VERSION 5.8 ;
BUSBITCHARS "[]" ;
DIVIDERCHAR "/" ;

PROPERTYDEFINITIONS
  LAYER contactResistance REAL ;
END PROPERTYDEFINITIONS

UNITS
  DATABASE MICRONS 2000 ;
END UNITS
MANUFACTURINGGRID 0.0025 ;
LAYER OVERLAP
  TYPE OVERLAP ;
END OVERLAP

LAYER poly
  TYPE MASTERSLICE ;
END poly

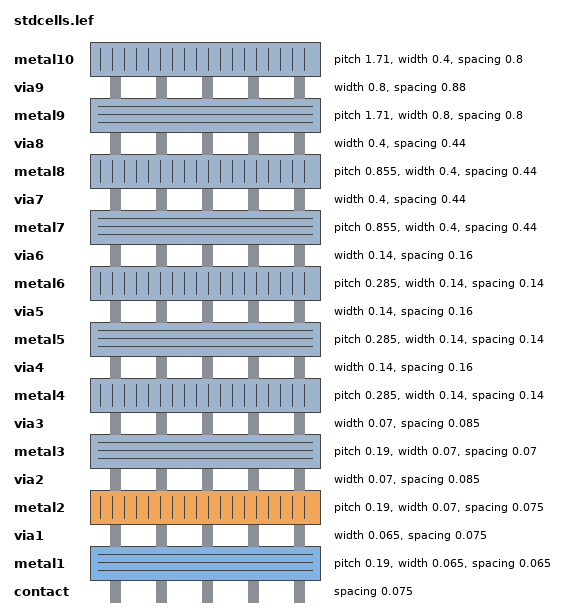
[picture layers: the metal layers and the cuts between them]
LAYER contact
  TYPE CUT ;
  SPACING 0.075 ;
  PROPERTY contactResistance 10.5 ;
END contact

LAYER metal1
  TYPE ROUTING ;
  DIRECTION HORIZONTAL ;
  PITCH 0.19 0.19 ;
  WIDTH 0.065 ;
  SPACING 0.065 ;
  SPACING 0.065 SAMENET ;
  RESISTANCE RPERSQ 0.38 ;
END metal1

LAYER via1
  TYPE CUT ;
  SPACING 0.075 ;
  WIDTH 0.065 ;
  PROPERTY contactResistance 5.69 ;
END via1

LAYER metal2
  TYPE ROUTING ;
  DIRECTION VERTICAL ;
  PITCH 0.19 0.19 ;
  WIDTH 0.07 ;
  SPACING 0.075 ;
  SPACING 0.07 SAMENET ;
  RESISTANCE RPERSQ 0.25 ;
END metal2

LAYER via2
  TYPE CUT ;
  SPACING 0.085 ;
  WIDTH 0.07 ;
  PROPERTY contactResistance 11.39 ;
END via2

LAYER metal3
  TYPE ROUTING ;
  DIRECTION HORIZONTAL ;
  PITCH 0.19 0.19 ;
  WIDTH 0.07 ;
  SPACING 0.07 ;
  SPACING 0.07 SAMENET ;
  RESISTANCE RPERSQ 0.25 ;
END metal3

LAYER via3
  TYPE CUT ;
  SPACING 0.085 ;
  WIDTH 0.07 ;
  PROPERTY contactResistance 16.73 ;
END via3

LAYER metal4
  TYPE ROUTING ;
  DIRECTION VERTICAL ;
  PITCH 0.285 0.285 ;
  WIDTH 0.14 ;
  SPACING 0.14 ;
  SPACING 0.14 SAMENET ;
  RESISTANCE RPERSQ 0.25 ;
END metal4

LAYER via4
  TYPE CUT ;
  SPACING 0.16 ;
  WIDTH 0.14 ;
  PROPERTY contactResistance 21.44 ;
END via4

LAYER metal5
  TYPE ROUTING ;
  DIRECTION HORIZONTAL ;
  PITCH 0.285 0.285 ;
  WIDTH 0.14 ;
  SPACING 0.14 ;
  SPACING 0.14 SAMENET ;
  RESISTANCE RPERSQ 0.25 ;
END metal5

LAYER via5
  TYPE CUT ;
  SPACING 0.16 ;
  WIDTH 0.14 ;
  PROPERTY contactResistance 24.08 ;
END via5

LAYER metal6
  TYPE ROUTING ;
  DIRECTION VERTICAL ;
  PITCH 0.285 0.285 ;
  WIDTH 0.14 ;
  SPACING 0.14 ;
  SPACING 0.14 SAMENET ;
  RESISTANCE RPERSQ 0.25 ;
END metal6

LAYER via6
  TYPE CUT ;
  SPACING 0.16 ;
  WIDTH 0.14 ;
  PROPERTY contactResistance 11.39 ;
END via6

LAYER metal7
  TYPE ROUTING ;
  DIRECTION HORIZONTAL ;
  PITCH 0.855 0.855 ;
  WIDTH 0.4 ;
  SPACING 0.44 ;
  SPACING 0.44 SAMENET ;
  RESISTANCE RPERSQ 0.25 ;
END metal7

LAYER via7
  TYPE CUT ;
  SPACING 0.44 ;
  WIDTH 0.4 ;
  PROPERTY contactResistance 5.69 ;
END via7

LAYER metal8
  TYPE ROUTING ;
  DIRECTION VERTICAL ;
  PITCH 0.855 0.855 ;
  WIDTH 0.4 ;
  SPACING 0.44 ;
  SPACING 0.44 SAMENET ;
  RESISTANCE RPERSQ 0.25 ;
END metal8

LAYER via8
  TYPE CUT ;
  SPACING 0.44 ;
  WIDTH 0.4 ;
  PROPERTY contactResistance 16.73 ;
END via8

LAYER metal9
  TYPE ROUTING ;
  DIRECTION HORIZONTAL ;
  PITCH 1.71 1.71 ;
  WIDTH 0.8 ;
  SPACING 0.8 ;
  SPACING 0.8 SAMENET ;
  RESISTANCE RPERSQ 0.21 ;
END metal9

LAYER via9
  TYPE CUT ;
  SPACING 0.88 ;
  WIDTH 0.8 ;
  PROPERTY contactResistance 21.44 ;
END via9

LAYER metal10
  TYPE ROUTING ;
  DIRECTION VERTICAL ;
  PITCH 1.71 1.71 ;
  WIDTH 0.4 ;
  SPACING 0.8 ;
  SPACING 0.8 SAMENET ;
  RESISTANCE RPERSQ 0.21 ;
END metal10

VIARULE M2_M1 GENERATE
  LAYER metal1 ;
    ENCLOSURE 0 0.035 ;
  LAYER metal2 ;
    ENCLOSURE 0 0.035 ;
  LAYER via1 ;
    RECT -0.0325 -0.0325 0.0325 0.0325 ;
    SPACING 0.14 BY 0.14 ;
END M2_M1

VIARULE M3_M2 GENERATE
  LAYER metal2 ;
    ENCLOSURE 0 0.035 ;
  LAYER metal3 ;
    ENCLOSURE 0 0.035 ;
  LAYER via2 ;
    RECT -0.035 -0.035 0.035 0.035 ;
    SPACING 0.155 BY 0.155 ;
END M3_M2

VIARULE M4_M3 GENERATE
  LAYER metal3 ;
    ENCLOSURE 0 0.035 ;
  LAYER metal4 ;
    ENCLOSURE 0 0 ;
  LAYER via3 ;
    RECT -0.035 -0.035 0.035 0.035 ;
    SPACING 0.155 BY 0.155 ;
END M4_M3

VIARULE M5_M4 GENERATE
  LAYER metal4 ;
    ENCLOSURE 0 0 ;
  LAYER metal5 ;
    ENCLOSURE 0 0 ;
  LAYER via4 ;
    RECT -0.07 -0.07 0.07 0.07 ;
    SPACING 0.3 BY 0.3 ;
END M5_M4

VIARULE M6_M5 GENERATE
  LAYER metal5 ;
    ENCLOSURE 0 0 ;
  LAYER metal6 ;
    ENCLOSURE 0 0 ;
  LAYER via5 ;
    RECT -0.07 -0.07 0.07 0.07 ;
    SPACING 0.3 BY 0.3 ;
END M6_M5

VIARULE M7_M6 GENERATE
  LAYER metal6 ;
    ENCLOSURE 0 0 ;
  LAYER metal7 ;
    ENCLOSURE 0.13 0.13 ;
  LAYER via6 ;
    RECT -0.07 -0.07 0.07 0.07 ;
    SPACING 0.3 BY 0.3 ;
END M7_M6

VIARULE M8_M7 GENERATE
  LAYER metal7 ;
    ENCLOSURE 0 0 ;
  LAYER metal8 ;
    ENCLOSURE 0 0 ;
  LAYER via7 ;
    RECT -0.2 -0.2 0.2 0.2 ;
    SPACING 0.8 BY 0.8 ;
END M8_M7

VIARULE M9_M8 GENERATE
  LAYER metal8 ;
    ENCLOSURE 0 0 ;
  LAYER metal9 ;
    ENCLOSURE 0.2 0.2 ;
  LAYER via8 ;
    RECT -0.2 -0.2 0.2 0.2 ;
    SPACING 0.8 BY 0.8 ;
END M9_M8

VIARULE M10_M9 GENERATE
  LAYER metal9 ;
    ENCLOSURE 0 0 ;
  LAYER metal10 ;
    ENCLOSURE 0 0 ;
  LAYER via9 ;
    RECT -0.4 -0.4 0.4 0.4 ;
    SPACING 1.6 BY 1.6 ;
END M10_M9

VIARULE M1_POLY GENERATE
  LAYER poly ;
    ENCLOSURE 0 0 ;
  LAYER metal1 ;
    ENCLOSURE 0 0.035 ;
  LAYER contact ;
    RECT -0.0325 -0.0325 0.0325 0.0325 ;
    SPACING 0.14 BY 0.14 ;
END M1_POLY

VIA M2_M1_via DEFAULT
  LAYER metal1 ;
    RECT -0.0675 -0.0325 0.0675 0.0325 ;
  LAYER via1 ;
    RECT -0.0325 -0.0325 0.0325 0.0325 ;
  LAYER metal2 ;
    RECT -0.035 -0.0675 0.035 0.0675 ;
END M2_M1_via

VIA M3_M2_via DEFAULT
  LAYER metal2 ;
    RECT -0.035 -0.07 0.035 0.07 ;
  LAYER via2 ;
    RECT -0.035 -0.035 0.035 0.035 ;
  LAYER metal3 ;
    RECT -0.07 -0.035 0.07 0.035 ;
END M3_M2_via

VIA M4_M3_via DEFAULT
  LAYER metal3 ;
    RECT -0.07 -0.035 0.07 0.035 ;
  LAYER via3 ;
    RECT -0.035 -0.035 0.035 0.035 ;
  LAYER metal4 ;
    RECT -0.07 -0.07 0.07 0.07 ;
END M4_M3_via

VIA M5_M4_via DEFAULT
  LAYER metal4 ;
    RECT -0.07 -0.07 0.07 0.07 ;
  LAYER via4 ;
    RECT -0.07 -0.07 0.07 0.07 ;
  LAYER metal5 ;
    RECT -0.07 -0.07 0.07 0.07 ;
END M5_M4_via

VIA M6_M5_via DEFAULT
  LAYER metal5 ;
    RECT -0.07 -0.07 0.07 0.07 ;
  LAYER via5 ;
    RECT -0.07 -0.07 0.07 0.07 ;
  LAYER metal6 ;
    RECT -0.07 -0.07 0.07 0.07 ;
END M6_M5_via

VIA M7_M6_via DEFAULT
  LAYER metal6 ;
    RECT -0.07 -0.07 0.07 0.07 ;
  LAYER via6 ;
    RECT -0.07 -0.07 0.07 0.07 ;
  LAYER metal7 ;
    RECT -0.2 -0.2 0.2 0.2 ;
END M7_M6_via

VIA M8_M7_via DEFAULT
  LAYER metal7 ;
    RECT -0.2 -0.2 0.2 0.2 ;
  LAYER via7 ;
    RECT -0.2 -0.2 0.2 0.2 ;
  LAYER metal8 ;
    RECT -0.2 -0.2 0.2 0.2 ;
END M8_M7_via

VIA M9_M8_via DEFAULT
  LAYER metal8 ;
    RECT -0.2 -0.2 0.2 0.2 ;
  LAYER via8 ;
    RECT -0.2 -0.2 0.2 0.2 ;
  LAYER metal9 ;
    RECT -0.4 -0.4 0.4 0.4 ;
END M9_M8_via

VIA M10_M9_via DEFAULT
  LAYER metal9 ;
    RECT -0.4 -0.4 0.4 0.4 ;
  LAYER via9 ;
    RECT -0.4 -0.4 0.4 0.4 ;
  LAYER metal10 ;
    RECT -0.4 -0.4 0.4 0.4 ;
END M10_M9_via

VIA M2_M1_viaB DEFAULT
  LAYER metal1 ;
    RECT -0.0675 -0.0325 0.0675 0.0325 ;
  LAYER via1 ;
    RECT -0.0325 -0.0325 0.0325 0.0325 ;
  LAYER metal2 ;
    RECT -0.0675 -0.035 0.0675 0.035 ;
END M2_M1_viaB

VIA M2_M1_viaC DEFAULT
  LAYER metal1 ;
    RECT -0.0325 -0.0675 0.0325 0.0675 ;
  LAYER via1 ;
    RECT -0.0325 -0.0325 0.0325 0.0325 ;
  LAYER metal2 ;
    RECT -0.035 -0.0675 0.035 0.0675 ;
END M2_M1_viaC

VIA M3_M2_viaB DEFAULT
  LAYER metal2 ;
    RECT -0.035 -0.07 0.035 0.07 ;
  LAYER via2 ;
    RECT -0.035 -0.035 0.035 0.035 ;
  LAYER metal3 ;
    RECT -0.035 -0.07 0.035 0.07 ;
END M3_M2_viaB

VIA M3_M2_viaC DEFAULT
  LAYER metal2 ;
    RECT -0.07 -0.035 0.07 0.035 ;
  LAYER via2 ;
    RECT -0.035 -0.035 0.035 0.035 ;
  LAYER metal3 ;
    RECT -0.07 -0.035 0.07 0.035 ;
END M3_M2_viaC

VIA M4_M3_viaB DEFAULT
  LAYER metal3 ;
    RECT -0.035 -0.07 0.035 0.07 ;
  LAYER via3 ;
    RECT -0.035 -0.035 0.035 0.035 ;
  LAYER metal4 ;
    RECT -0.07 -0.07 0.07 0.07 ;
END M4_M3_viaB

SITE CoreSite
  CLASS CORE ;
  SYMMETRY Y ;
  SIZE 0.005 BY 1.4 ;
END CoreSite

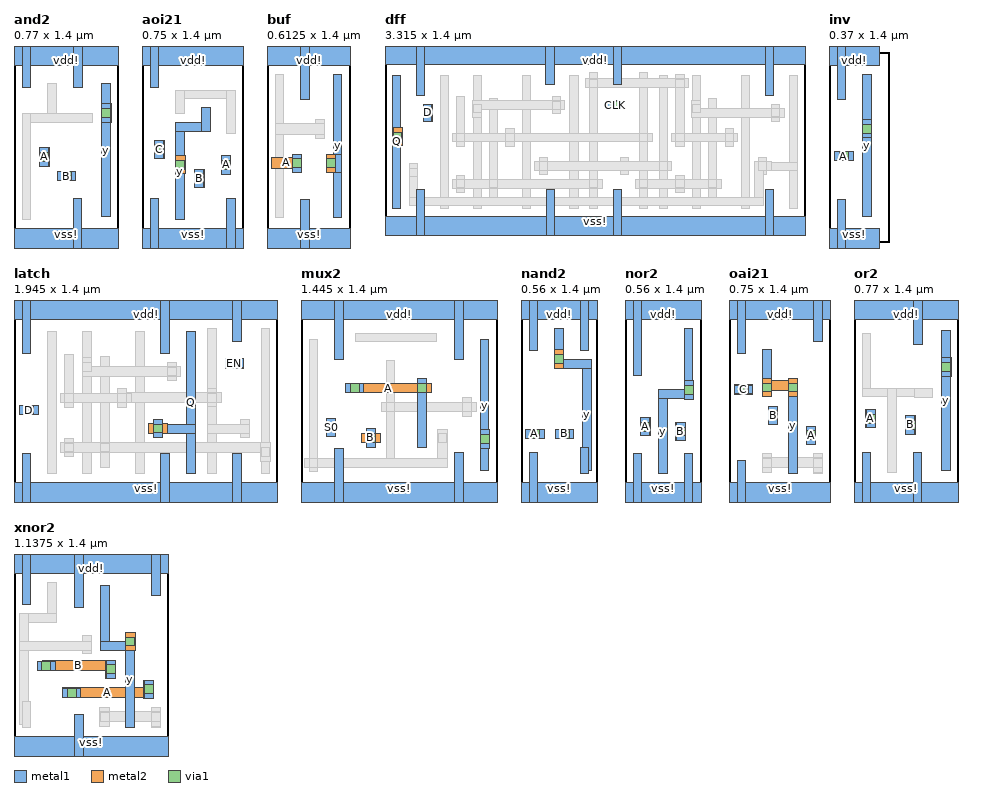
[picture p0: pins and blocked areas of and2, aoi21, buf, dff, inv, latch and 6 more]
MACRO and2
  CLASS CORE ;
  ORIGIN 0 -0.1 ;
  FOREIGN and2 0 0.1 ;
  SIZE 0.77 BY 1.4 ;
  SYMMETRY X Y ;
  SITE CoreSite ;
  PIN vdd!
    DIRECTION INOUT ;
    USE POWER ;
    SHAPE ABUTMENT ;
    PORT
      LAYER metal1 ;
        RECT 0 1.4 0.77 1.6 ;
        RECT 0.4375 1.24 0.5025 1.6 ;
        RECT 0.06 1.24 0.125 1.6 ;
    END
  END vdd!
  PIN vss!
    DIRECTION INOUT ;
    USE GROUND ;
    SHAPE ABUTMENT ;
    PORT
      LAYER metal1 ;
        RECT 0 0 0.77 0.2 ;
        RECT 0.435 0 0.5 0.4225 ;
    END
  END vss!
  PIN A
    DIRECTION INPUT ;
    USE SIGNAL ;
    PORT
      LAYER metal1 ;
        RECT 0.19 0.66 0.2575 0.795 ;
      LAYER metal2 ;
        RECT 0.19 0.66 0.26 0.795 ;
      LAYER via1 ;
        RECT 0.1925 0.695 0.2575 0.76 ;
    END
  END A
  PIN B
    DIRECTION INPUT ;
    USE SIGNAL ;
    PORT
      LAYER metal1 ;
        RECT 0.32 0.5525 0.455 0.6175 ;
      LAYER metal2 ;
        RECT 0.32 0.55 0.455 0.62 ;
      LAYER via1 ;
        RECT 0.355 0.5525 0.42 0.6175 ;
    END
  END B
  PIN y
    DIRECTION OUTPUT ;
    USE SIGNAL ;
    PORT
      LAYER metal1 ;
        RECT 0.645 0.9825 0.7125 1.1175 ;
        RECT 0.645 0.285 0.71 1.27 ;
      LAYER metal2 ;
        RECT 0.645 0.9825 0.715 1.1175 ;
      LAYER via1 ;
        RECT 0.6475 1.0175 0.7125 1.0825 ;
    END
  END y
  OBS
    LAYER metal1 ;
      RECT 0.25 0.9825 0.315 1.27 ;
      RECT 0.06 0.9825 0.58 1.0475 ;
      RECT 0.06 0.265 0.125 1.0475 ;
  END
END and2

MACRO aoi21
  CLASS CORE ;
  ORIGIN 0 -0.1 ;
  FOREIGN aoi21 0 0.1 ;
  SIZE 0.75 BY 1.4 ;
  SYMMETRY X Y ;
  SITE CoreSite ;
  PIN vdd!
    DIRECTION INOUT ;
    USE POWER ;
    SHAPE ABUTMENT ;
    PORT
      LAYER metal1 ;
        RECT 0 1.4 0.75 1.6 ;
        RECT 0.06 1.24 0.125 1.6 ;
    END
  END vdd!
  PIN vss!
    DIRECTION INOUT ;
    USE GROUND ;
    SHAPE ABUTMENT ;
    PORT
      LAYER metal1 ;
        RECT 0 0 0.75 0.2 ;
        RECT 0.625 0 0.69 0.42 ;
        RECT 0.06 0 0.125 0.42 ;
    END
  END vss!
  PIN A
    DIRECTION INPUT ;
    USE SIGNAL ;
    PORT
      LAYER metal1 ;
        RECT 0.5875 0.6 0.6525 0.735 ;
      LAYER metal2 ;
        RECT 0.585 0.6 0.655 0.735 ;
      LAYER via1 ;
        RECT 0.5875 0.635 0.6525 0.7 ;
    END
  END A
  PIN B
    DIRECTION INPUT ;
    USE SIGNAL ;
    PORT
      LAYER metal1 ;
        RECT 0.39 0.5025 0.455 0.6375 ;
      LAYER metal2 ;
        RECT 0.3875 0.5025 0.4575 0.6375 ;
      LAYER via1 ;
        RECT 0.39 0.5375 0.455 0.6025 ;
    END
  END B
  PIN C
    DIRECTION INPUT ;
    USE SIGNAL ;
    PORT
      LAYER metal1 ;
        RECT 0.095 0.715 0.16 0.85 ;
      LAYER metal2 ;
        RECT 0.0925 0.715 0.165 0.85 ;
      LAYER via1 ;
        RECT 0.095 0.75 0.16 0.815 ;
    END
  END C
  PIN y
    DIRECTION OUTPUT ;
    USE SIGNAL ;
    PORT
      LAYER metal1 ;
        RECT 0.4375 0.915 0.5025 1.09 ;
        RECT 0.25 0.915 0.5025 0.98 ;
        RECT 0.25 0.265 0.315 0.98 ;
      LAYER metal2 ;
        RECT 0.2475 0.6025 0.3175 0.7375 ;
      LAYER via1 ;
        RECT 0.25 0.6375 0.315 0.7025 ;
    END
  END y
  OBS
    LAYER metal1 ;
      RECT 0.2475 1.155 0.69 1.22 ;
      RECT 0.625 0.9025 0.69 1.22 ;
      RECT 0.2475 1.0475 0.3125 1.22 ;
  END
END aoi21

MACRO buf
  CLASS CORE ;
  ORIGIN 0 -0.1 ;
  FOREIGN buf 0 0.1 ;
  SIZE 0.6125 BY 1.4 ;
  SYMMETRY X Y ;
  SITE CoreSite ;
  PIN vdd!
    DIRECTION INOUT ;
    USE POWER ;
    SHAPE ABUTMENT ;
    PORT
      LAYER metal1 ;
        RECT 0 1.4 0.6125 1.6 ;
        RECT 0.245 1.15 0.31 1.6 ;
    END
  END vdd!
  PIN vss!
    DIRECTION INOUT ;
    USE GROUND ;
    SHAPE ABUTMENT ;
    PORT
      LAYER metal1 ;
        RECT 0 0 0.6125 0.2 ;
        RECT 0.245 0 0.31 0.415 ;
    END
  END vss!
  PIN A
    DIRECTION INPUT ;
    USE SIGNAL ;
    PORT
      LAYER metal1 ;
        RECT 0.19 0.6125 0.255 0.7475 ;
      LAYER metal2 ;
        RECT 0.1875 0.6125 0.2575 0.7475 ;
        RECT 0.0325 0.645 0.2575 0.725 ;
      LAYER via1 ;
        RECT 0.19 0.6475 0.255 0.7125 ;
    END
  END A
  PIN y
    DIRECTION OUTPUT ;
    USE SIGNAL ;
    PORT
      LAYER metal1 ;
        RECT 0.4875 0.2825 0.5525 1.335 ;
        RECT 0.4375 0.6125 0.5525 0.7475 ;
      LAYER metal2 ;
        RECT 0.435 0.6125 0.505 0.7475 ;
      LAYER via1 ;
        RECT 0.4375 0.6475 0.5025 0.7125 ;
    END
  END y
  OBS
    LAYER metal1 ;
      RECT 0.06 0.2825 0.125 1.335 ;
      RECT 0.3575 0.865 0.4225 1 ;
      RECT 0.06 0.89 0.4225 0.97 ;
  END
END buf

MACRO dff
  CLASS CORE ;
  ORIGIN 0.19 -0.1 ;
  FOREIGN dff -0.19 0.1 ;
  SIZE 3.315 BY 1.4 ;
  SYMMETRY X Y ;
  SITE CoreSite ;
  PIN vdd!
    DIRECTION INOUT ;
    USE POWER ;
    SHAPE ABUTMENT ;
    PORT
      LAYER metal1 ;
        RECT -0.19 1.4 3.125 1.6 ;
        RECT 2.81 1.15 2.875 1.6 ;
        RECT 1.6125 1.24 1.6775 1.6 ;
        RECT 1.08 1.24 1.145 1.6 ;
        RECT 0.06 1.15 0.125 1.6 ;
    END
  END vdd!
  PIN vss!
    DIRECTION INOUT ;
    USE GROUND ;
    SHAPE ABUTMENT ;
    PORT
      LAYER metal1 ;
        RECT -0.19 0 3.125 0.2 ;
        RECT 2.8125 0 2.8775 0.415 ;
        RECT 1.6125 0 1.6775 0.4125 ;
        RECT 1.0825 0 1.1475 0.415 ;
        RECT 0.06 0 0.125 0.415 ;
    END
  END vss!
  PIN CLK
    DIRECTION INPUT ;
    USE SIGNAL ;
    PORT
      LAYER metal1 ;
        RECT 1.555 1.045 1.69 1.11 ;
      LAYER metal2 ;
        RECT 1.555 1.0425 1.69 1.1125 ;
      LAYER via1 ;
        RECT 1.59 1.045 1.655 1.11 ;
    END
  END CLK
  PIN D
    DIRECTION INPUT ;
    USE SIGNAL ;
    PORT
      LAYER metal1 ;
        RECT 0.115 0.95 0.18 1.085 ;
      LAYER metal2 ;
        RECT 0.1125 0.95 0.1825 1.085 ;
      LAYER via1 ;
        RECT 0.115 0.985 0.18 1.05 ;
    END
  END D
  PIN Q
    DIRECTION OUTPUT ;
    USE SIGNAL ;
    PORT
      LAYER metal1 ;
        RECT -0.13 0.7625 -0.0575 0.8975 ;
        RECT -0.13 0.265 -0.065 1.3125 ;
      LAYER metal2 ;
        RECT -0.125 0.7625 -0.055 0.8975 ;
      LAYER via1 ;
        RECT -0.1225 0.7975 -0.0575 0.8625 ;
    END
  END Q
  OBS
    LAYER metal1 ;
      RECT 3 0.265 3.065 1.3125 ;
      RECT 2.7575 0.53 2.8225 0.665 ;
      RECT 2.7575 0.5625 3.065 0.6275 ;
      RECT 1.425 0.265 1.49 1.335 ;
      RECT 1.6675 0.53 1.7325 0.665 ;
      RECT 1.425 0.5625 1.7325 0.6275 ;
      RECT 1.27 0.265 1.335 1.3125 ;
      RECT 1.0275 0.53 1.0925 0.665 ;
      RECT 1.0275 0.5625 1.335 0.6275 ;
      RECT 2.86 0.95 2.925 1.085 ;
      RECT 2.625 0.265 2.69 1.3125 ;
      RECT 2.495 0.755 2.56 0.89 ;
      RECT 2.365 0.3125 2.43 1.1275 ;
      RECT 2.235 0.265 2.3 1.3125 ;
      RECT 2.105 0.39 2.17 0.525 ;
      RECT 2.105 0.755 2.17 1.3175 ;
      RECT 1.975 0.265 2.04 1.3125 ;
      RECT 1.82 0.265 1.885 1.335 ;
      RECT 1.13 1.01 1.195 1.145 ;
      RECT 0.895 0.265 0.96 1.3125 ;
      RECT 0.765 0.755 0.83 0.89 ;
      RECT 0.635 0.3125 0.7 1.1275 ;
      RECT 0.505 0.265 0.57 1.3125 ;
      RECT 0.375 0.39 0.44 0.525 ;
      RECT 0.375 0.755 0.44 1.145 ;
      RECT 0.245 0.265 0.31 1.3125 ;
      RECT 0.0025 0.48 0.0675 0.615 ;
    LAYER metal2 ;
      RECT 2.2325 0.9825 2.3025 1.1175 ;
      RECT 2.2325 0.9825 2.96 1.0525 ;
      RECT 2.7225 0.5625 2.8575 0.6325 ;
      RECT 0 0.2825 0.07 0.615 ;
      RECT 2.7225 0.2825 2.795 0.6325 ;
      RECT 0 0.2825 2.795 0.3525 ;
      RECT 0.5025 0.9825 0.5725 1.1175 ;
      RECT 0.5025 1.0425 1.23 1.1125 ;
      RECT 2.07 0.7875 2.595 0.8575 ;
      RECT 1.785 0.4225 2.465 0.4925 ;
      RECT 1.39 1.215 2.205 1.285 ;
      RECT 0.9925 0.5625 2.075 0.6325 ;
      RECT 0.34 0.7875 1.92 0.8575 ;
      RECT 0.34 0.4225 1.525 0.4925 ;
    LAYER via1 ;
      RECT 2.86 0.985 2.925 1.05 ;
      RECT 2.7575 0.565 2.8225 0.63 ;
      RECT 2.495 0.79 2.56 0.855 ;
      RECT 2.365 0.425 2.43 0.49 ;
      RECT 2.235 1.0175 2.3 1.0825 ;
      RECT 2.105 0.425 2.17 0.49 ;
      RECT 2.105 0.79 2.17 0.855 ;
      RECT 2.105 1.2175 2.17 1.2825 ;
      RECT 1.975 0.565 2.04 0.63 ;
      RECT 1.82 0.425 1.885 0.49 ;
      RECT 1.82 0.79 1.885 0.855 ;
      RECT 1.425 0.425 1.49 0.49 ;
      RECT 1.425 1.2175 1.49 1.2825 ;
      RECT 1.13 1.045 1.195 1.11 ;
      RECT 1.0275 0.565 1.0925 0.63 ;
      RECT 0.765 0.79 0.83 0.855 ;
      RECT 0.635 0.425 0.7 0.49 ;
      RECT 0.505 1.0175 0.57 1.0825 ;
      RECT 0.375 0.425 0.44 0.49 ;
      RECT 0.375 0.79 0.44 0.855 ;
      RECT 0.0025 0.515 0.0675 0.58 ;
  END
END dff

MACRO inv
  CLASS CORE ;
  ORIGIN 0 -0.1 ;
  FOREIGN inv 0 0.1 ;
  SIZE 0.37 BY 1.4 ;
  SYMMETRY X Y ;
  SITE CoreSite ;
  PIN vdd!
    DIRECTION INOUT ;
    USE POWER ;
    SHAPE ABUTMENT ;
    PORT
      LAYER metal1 ;
        RECT 0 1.4 0.37 1.6 ;
        RECT 0.06 1.15 0.125 1.6 ;
    END
  END vdd!
  PIN vss!
    DIRECTION INOUT ;
    USE GROUND ;
    SHAPE ABUTMENT ;
    PORT
      LAYER metal1 ;
        RECT 0 0 0.37 0.2 ;
        RECT 0.06 0 0.125 0.415 ;
    END
  END vss!
  PIN A
    DIRECTION INPUT ;
    USE SIGNAL ;
    PORT
      LAYER metal1 ;
        RECT 0.0425 0.7 0.1775 0.765 ;
      LAYER metal2 ;
        RECT 0.0425 0.6975 0.1775 0.7675 ;
      LAYER via1 ;
        RECT 0.0775 0.7 0.1425 0.765 ;
    END
  END A
  PIN y
    DIRECTION OUTPUT ;
    USE SIGNAL ;
    PORT
      LAYER metal1 ;
        RECT 0.245 0.8675 0.3125 1.0025 ;
        RECT 0.245 0.2875 0.31 1.335 ;
      LAYER metal2 ;
        RECT 0.245 0.8675 0.315 1.0025 ;
      LAYER via1 ;
        RECT 0.2475 0.9025 0.3125 0.9675 ;
    END
  END y
END inv

MACRO latch
  CLASS CORE ;
  ORIGIN 0 -0.1 ;
  FOREIGN latch 0 0.1 ;
  SIZE 1.945 BY 1.4 ;
  SYMMETRY X Y ;
  SITE CoreSite ;
  PIN vdd!
    DIRECTION INOUT ;
    USE POWER ;
    SHAPE ABUTMENT ;
    PORT
      LAYER metal1 ;
        RECT 0 1.4 1.945 1.6 ;
        RECT 1.6125 1.24 1.6775 1.6 ;
        RECT 1.08 1.15 1.145 1.6 ;
        RECT 0.06 1.15 0.125 1.6 ;
    END
  END vdd!
  PIN vss!
    DIRECTION INOUT ;
    USE GROUND ;
    SHAPE ABUTMENT ;
    PORT
      LAYER metal1 ;
        RECT 0 0 1.945 0.2 ;
        RECT 1.6125 0 1.6775 0.4125 ;
        RECT 1.0825 0 1.1475 0.415 ;
        RECT 0.06 0 0.125 0.415 ;
    END
  END vss!
  PIN D
    DIRECTION INPUT ;
    USE SIGNAL ;
    PORT
      LAYER metal1 ;
        RECT 0.0425 0.7 0.1775 0.765 ;
      LAYER metal2 ;
        RECT 0.0425 0.6975 0.1775 0.7675 ;
      LAYER via1 ;
        RECT 0.0775 0.7 0.1425 0.765 ;
    END
  END D
  PIN EN
    DIRECTION INPUT ;
    USE SIGNAL ;
    PORT
      LAYER metal1 ;
        RECT 1.555 1.045 1.69 1.11 ;
      LAYER metal2 ;
        RECT 1.555 1.0425 1.69 1.1125 ;
      LAYER via1 ;
        RECT 1.59 1.045 1.655 1.11 ;
    END
  END EN
  PIN Q
    DIRECTION OUTPUT ;
    USE SIGNAL ;
    PORT
      LAYER metal1 ;
        RECT 1.27 0.265 1.335 1.3125 ;
        RECT 1.0275 0.5625 1.335 0.6275 ;
        RECT 1.0275 0.53 1.0925 0.665 ;
      LAYER metal2 ;
        RECT 0.9925 0.5625 1.1275 0.6325 ;
      LAYER via1 ;
        RECT 1.0275 0.565 1.0925 0.63 ;
    END
  END Q
  OBS
    LAYER metal1 ;
      RECT 1.425 0.265 1.49 1.335 ;
      RECT 1.425 0.7575 1.4925 0.8925 ;
      RECT 1.6675 0.53 1.7325 0.665 ;
      RECT 1.425 0.5625 1.7325 0.6275 ;
      RECT 1.82 0.265 1.885 1.335 ;
      RECT 1.13 0.95 1.195 1.085 ;
      RECT 0.895 0.265 0.96 1.3125 ;
      RECT 0.765 0.755 0.83 0.89 ;
      RECT 0.635 0.3125 0.7 1.1275 ;
      RECT 0.505 0.265 0.57 1.3125 ;
      RECT 0.375 0.39 0.44 0.525 ;
      RECT 0.375 0.755 0.44 1.145 ;
      RECT 0.245 0.265 0.31 1.3125 ;
    LAYER metal2 ;
      RECT 0.34 0.4225 1.8875 0.4925 ;
      RECT 1.8175 0.3575 1.8875 0.4925 ;
      RECT 0.8275 0.79 1.5275 0.86 ;
      RECT 0.34 0.7875 0.865 0.8575 ;
      RECT 0.5025 0.9825 0.5725 1.1175 ;
      RECT 0.5025 0.9825 1.23 1.0525 ;
    LAYER via1 ;
      RECT 1.82 0.3925 1.885 0.4575 ;
      RECT 1.4275 0.7925 1.4925 0.8575 ;
      RECT 1.13 0.985 1.195 1.05 ;
      RECT 0.765 0.79 0.83 0.855 ;
      RECT 0.635 0.425 0.7 0.49 ;
      RECT 0.505 1.0175 0.57 1.0825 ;
      RECT 0.375 0.425 0.44 0.49 ;
      RECT 0.375 0.79 0.44 0.855 ;
  END
END latch

MACRO mux2
  CLASS CORE ;
  ORIGIN 0.19 -0.1 ;
  FOREIGN mux2 -0.19 0.1 ;
  SIZE 1.445 BY 1.4 ;
  SYMMETRY X Y ;
  SITE CoreSite ;
  PIN vdd!
    DIRECTION INOUT ;
    USE POWER ;
    SHAPE ABUTMENT ;
    PORT
      LAYER metal1 ;
        RECT -0.19 1.4 1.255 1.6 ;
        RECT 0.9425 1.1075 1.0075 1.6 ;
        RECT 0.06 1.1025 0.125 1.6 ;
    END
  END vdd!
  PIN vss!
    DIRECTION INOUT ;
    USE GROUND ;
    SHAPE ABUTMENT ;
    PORT
      LAYER metal1 ;
        RECT -0.19 0 1.255 0.2 ;
        RECT 0.9425 0 1.0075 0.4225 ;
        RECT 0.06 0 0.125 0.45 ;
    END
  END vss!
  PIN A
    DIRECTION INPUT ;
    USE SIGNAL ;
    PORT
      LAYER metal1 ;
        RECT 0.67 0.4575 0.735 0.9625 ;
        RECT 0.1375 0.8625 0.2725 0.93 ;
      LAYER metal2 ;
        RECT 0.1375 0.86 0.77 0.93 ;
      LAYER via1 ;
        RECT 0.1725 0.8625 0.2375 0.9275 ;
        RECT 0.67 0.8625 0.735 0.9275 ;
    END
  END A
  PIN B
    DIRECTION INPUT ;
    USE SIGNAL ;
    PORT
      LAYER metal1 ;
        RECT 0.2925 0.46 0.3575 0.595 ;
      LAYER metal2 ;
        RECT 0.2575 0.4925 0.3925 0.5625 ;
      LAYER via1 ;
        RECT 0.2925 0.495 0.3575 0.56 ;
    END
  END B
  PIN S0
    DIRECTION INPUT ;
    USE SIGNAL ;
    PORT
      LAYER metal1 ;
        RECT 0 0.5375 0.065 0.6725 ;
      LAYER metal2 ;
        RECT -0.0025 0.5375 0.0675 0.6725 ;
      LAYER via1 ;
        RECT 0 0.5725 0.065 0.6375 ;
    END
  END S0
  PIN y
    DIRECTION OUTPUT ;
    USE SIGNAL ;
    PORT
      LAYER metal1 ;
        RECT 1.13 0.4525 1.1975 0.5875 ;
        RECT 1.13 0.285 1.195 1.255 ;
      LAYER metal2 ;
        RECT 1.13 0.4525 1.2 0.5875 ;
      LAYER via1 ;
        RECT 1.1325 0.4875 1.1975 0.5525 ;
    END
  END y
  OBS
    LAYER metal1 ;
      RECT 1 0.6875 1.065 0.8225 ;
      RECT 0.82 0.4575 0.885 0.5925 ;
      RECT 0.215 1.235 0.81 1.3 ;
      RECT 0.4375 0.3075 0.5025 1.0975 ;
      RECT -0.13 0.2775 -0.065 1.255 ;
    LAYER metal2 ;
      RECT 0.8175 0.31 0.8875 0.5925 ;
      RECT -0.165 0.31 0.8875 0.38 ;
      RECT 0.4025 0.72 1.1 0.79 ;
    LAYER via1 ;
      RECT 1 0.7225 1.065 0.7875 ;
      RECT 0.82 0.4925 0.885 0.5575 ;
      RECT 0.4375 0.7225 0.5025 0.7875 ;
      RECT -0.13 0.3125 -0.065 0.3775 ;
  END
END mux2

MACRO nand2
  CLASS CORE ;
  ORIGIN 0 -0.1 ;
  FOREIGN nand2 0 0.1 ;
  SIZE 0.56 BY 1.4 ;
  SYMMETRY X Y ;
  SITE CoreSite ;
  PIN vdd!
    DIRECTION INOUT ;
    USE POWER ;
    SHAPE ABUTMENT ;
    PORT
      LAYER metal1 ;
        RECT 0 1.4 0.56 1.6 ;
        RECT 0.435 1.175 0.5 1.6 ;
        RECT 0.06 1.175 0.125 1.6 ;
    END
  END vdd!
  PIN vss!
    DIRECTION INOUT ;
    USE GROUND ;
    SHAPE ABUTMENT ;
    PORT
      LAYER metal1 ;
        RECT 0 0 0.56 0.2 ;
        RECT 0.06 0 0.125 0.4225 ;
    END
  END vss!
  PIN A
    DIRECTION INPUT ;
    USE SIGNAL ;
    PORT
      LAYER metal1 ;
        RECT 0.035 0.525 0.17 0.59 ;
      LAYER metal2 ;
        RECT 0.035 0.5225 0.17 0.5925 ;
      LAYER via1 ;
        RECT 0.07 0.525 0.135 0.59 ;
    END
  END A
  PIN B
    DIRECTION INPUT ;
    USE SIGNAL ;
    PORT
      LAYER metal1 ;
        RECT 0.255 0.525 0.39 0.59 ;
      LAYER metal2 ;
        RECT 0.255 0.5225 0.39 0.5925 ;
      LAYER via1 ;
        RECT 0.29 0.525 0.355 0.59 ;
    END
  END B
  PIN y
    DIRECTION OUTPUT ;
    USE SIGNAL ;
    PORT
      LAYER metal1 ;
        RECT 0.2475 1.0425 0.52 1.1075 ;
        RECT 0.455 0.2875 0.52 1.1075 ;
        RECT 0.435 0.2675 0.5 0.46 ;
        RECT 0.2475 1.0425 0.3125 1.335 ;
      LAYER metal2 ;
        RECT 0.245 1.0425 0.315 1.1775 ;
      LAYER via1 ;
        RECT 0.2475 1.0775 0.3125 1.1425 ;
    END
  END y
END nand2

MACRO nor2
  CLASS CORE ;
  ORIGIN 0 -0.1 ;
  FOREIGN nor2 0 0.1 ;
  SIZE 0.56 BY 1.4 ;
  SYMMETRY X Y ;
  SITE CoreSite ;
  PIN vdd!
    DIRECTION INOUT ;
    USE POWER ;
    SHAPE ABUTMENT ;
    PORT
      LAYER metal1 ;
        RECT 0 1.4 0.56 1.6 ;
        RECT 0.06 0.99 0.125 1.6 ;
    END
  END vdd!
  PIN vss!
    DIRECTION INOUT ;
    USE GROUND ;
    SHAPE ABUTMENT ;
    PORT
      LAYER metal1 ;
        RECT 0 0 0.56 0.2 ;
        RECT 0.435 0 0.5 0.415 ;
        RECT 0.06 0 0.125 0.415 ;
    END
  END vss!
  PIN A
    DIRECTION INPUT ;
    USE SIGNAL ;
    PORT
      LAYER metal1 ;
        RECT 0.1175 0.5425 0.1825 0.6775 ;
      LAYER metal2 ;
        RECT 0.115 0.5425 0.185 0.6775 ;
      LAYER via1 ;
        RECT 0.1175 0.5775 0.1825 0.6425 ;
    END
  END A
  PIN B
    DIRECTION INPUT ;
    USE SIGNAL ;
    PORT
      LAYER metal1 ;
        RECT 0.3775 0.5075 0.4425 0.6425 ;
      LAYER metal2 ;
        RECT 0.375 0.5075 0.445 0.6425 ;
      LAYER via1 ;
        RECT 0.3775 0.5425 0.4425 0.6075 ;
    END
  END B
  PIN y
    DIRECTION OUTPUT ;
    USE SIGNAL ;
    PORT
      LAYER metal1 ;
        RECT 0.4375 0.8125 0.5025 0.9475 ;
        RECT 0.435 0.8175 0.5 1.335 ;
        RECT 0.2475 0.8175 0.5025 0.8825 ;
        RECT 0.2475 0.265 0.3125 0.8825 ;
      LAYER metal2 ;
        RECT 0.435 0.8125 0.505 0.9475 ;
      LAYER via1 ;
        RECT 0.4375 0.8475 0.5025 0.9125 ;
    END
  END y
END nor2

MACRO oai21
  CLASS CORE ;
  ORIGIN 0 -0.1 ;
  FOREIGN oai21 0 0.1 ;
  SIZE 0.75 BY 1.4 ;
  SYMMETRY X Y ;
  SITE CoreSite ;
  PIN vdd!
    DIRECTION INOUT ;
    USE POWER ;
    SHAPE ABUTMENT ;
    PORT
      LAYER metal1 ;
        RECT 0 1.4 0.75 1.6 ;
        RECT 0.625 1.24 0.69 1.6 ;
        RECT 0.06 1.1475 0.125 1.6 ;
    END
  END vdd!
  PIN vss!
    DIRECTION INOUT ;
    USE GROUND ;
    SHAPE ABUTMENT ;
    PORT
      LAYER metal1 ;
        RECT 0 0 0.75 0.2 ;
        RECT 0.06 0 0.125 0.36 ;
    END
  END vss!
  PIN A
    DIRECTION INPUT ;
    USE SIGNAL ;
    PORT
      LAYER metal1 ;
        RECT 0.5725 0.48 0.6375 0.615 ;
      LAYER metal2 ;
        RECT 0.57 0.48 0.64 0.615 ;
      LAYER via1 ;
        RECT 0.5725 0.515 0.6375 0.58 ;
    END
  END A
  PIN B
    DIRECTION INPUT ;
    USE SIGNAL ;
    PORT
      LAYER metal1 ;
        RECT 0.2925 0.6275 0.3575 0.7625 ;
      LAYER metal2 ;
        RECT 0.29 0.6275 0.36 0.7625 ;
      LAYER via1 ;
        RECT 0.2925 0.6625 0.3575 0.7275 ;
    END
  END B
  PIN C
    DIRECTION INPUT ;
    USE SIGNAL ;
    PORT
      LAYER metal1 ;
        RECT 0.04 0.8525 0.175 0.9175 ;
      LAYER metal2 ;
        RECT 0.04 0.85 0.175 0.92 ;
      LAYER via1 ;
        RECT 0.075 0.8525 0.14 0.9175 ;
    END
  END C
  PIN y
    DIRECTION OUTPUT ;
    USE SIGNAL ;
    PORT
      LAYER metal1 ;
        RECT 0.4375 0.265 0.5025 0.9675 ;
        RECT 0.2475 0.8325 0.3125 1.1775 ;
      LAYER metal2 ;
        RECT 0.435 0.8325 0.505 0.9675 ;
        RECT 0.245 0.8775 0.505 0.9475 ;
        RECT 0.245 0.8325 0.315 0.9675 ;
      LAYER via1 ;
        RECT 0.2475 0.8675 0.3125 0.9325 ;
        RECT 0.4375 0.8675 0.5025 0.9325 ;
    END
  END y
  OBS
    LAYER metal1 ;
      RECT 0.625 0.265 0.69 0.415 ;
      RECT 0.2475 0.275 0.3125 0.41 ;
    LAYER metal2 ;
      RECT 0.6225 0.275 0.6925 0.41 ;
      RECT 0.245 0.275 0.315 0.41 ;
      RECT 0.245 0.3125 0.6925 0.3825 ;
    LAYER via1 ;
      RECT 0.625 0.31 0.69 0.375 ;
      RECT 0.2475 0.31 0.3125 0.375 ;
  END
END oai21

MACRO or2
  CLASS CORE ;
  ORIGIN -0.0025 -0.1 ;
  FOREIGN or2 0.0025 0.1 ;
  SIZE 0.77 BY 1.4 ;
  SYMMETRY X Y ;
  SITE CoreSite ;
  PIN vdd!
    DIRECTION INOUT ;
    USE POWER ;
    SHAPE ABUTMENT ;
    PORT
      LAYER metal1 ;
        RECT 0.0025 1.4 0.7725 1.6 ;
        RECT 0.44 1.22 0.505 1.6 ;
    END
  END vdd!
  PIN vss!
    DIRECTION INOUT ;
    USE GROUND ;
    SHAPE ABUTMENT ;
    PORT
      LAYER metal1 ;
        RECT 0.0025 0 0.7725 0.2 ;
        RECT 0.4375 0 0.5025 0.4225 ;
        RECT 0.0625 0 0.1275 0.4225 ;
    END
  END vss!
  PIN A
    DIRECTION INPUT ;
    USE SIGNAL ;
    PORT
      LAYER metal1 ;
        RECT 0.0925 0.6025 0.1575 0.7375 ;
      LAYER metal2 ;
        RECT 0.09 0.6025 0.16 0.7375 ;
      LAYER via1 ;
        RECT 0.0925 0.6375 0.1575 0.7025 ;
    END
  END A
  PIN B
    DIRECTION INPUT ;
    USE SIGNAL ;
    PORT
      LAYER metal1 ;
        RECT 0.3875 0.5575 0.4525 0.6925 ;
        RECT 0.385 0.555 0.45 0.69 ;
      LAYER metal2 ;
        RECT 0.385 0.555 0.455 0.6925 ;
      LAYER via1 ;
        RECT 0.3875 0.5925 0.4525 0.6575 ;
    END
  END B
  PIN y
    DIRECTION OUTPUT ;
    USE SIGNAL ;
    PORT
      LAYER metal1 ;
        RECT 0.6475 0.9825 0.715 1.1175 ;
        RECT 0.6475 0.285 0.7125 1.3175 ;
      LAYER metal2 ;
        RECT 0.6475 0.9825 0.7175 1.1175 ;
      LAYER via1 ;
        RECT 0.65 1.0175 0.715 1.0825 ;
    END
  END y
  OBS
    LAYER metal1 ;
      RECT 0.0625 0.83 0.1275 1.3 ;
      RECT 0.0625 0.83 0.5175 0.895 ;
      RECT 0.4475 0.8275 0.5825 0.8925 ;
      RECT 0.2525 0.275 0.3175 0.895 ;
  END
END or2

MACRO xnor2
  CLASS CORE ;
  ORIGIN -0.0025 -0.1 ;
  FOREIGN xnor2 0.0025 0.1 ;
  SIZE 1.1375 BY 1.4 ;
  SYMMETRY X Y ;
  SITE CoreSite ;
  PIN vdd!
    DIRECTION INOUT ;
    USE POWER ;
    SHAPE ABUTMENT ;
    PORT
      LAYER metal1 ;
        RECT 0.0025 1.4 1.14 1.6 ;
        RECT 1.015 1.24 1.08 1.6 ;
        RECT 0.45 1.1475 0.515 1.6 ;
        RECT 0.0625 1.175 0.1275 1.6 ;
    END
  END vdd!
  PIN vss!
    DIRECTION INOUT ;
    USE GROUND ;
    SHAPE ABUTMENT ;
    PORT
      LAYER metal1 ;
        RECT 0.0025 0 1.14 0.2 ;
        RECT 0.45 0 0.515 0.36 ;
    END
  END vss!
  PIN A
    DIRECTION INPUT ;
    USE SIGNAL ;
    PORT
      LAYER metal1 ;
        RECT 0.9625 0.48 1.0275 0.615 ;
        RECT 0.36 0.49 0.495 0.555 ;
      LAYER metal2 ;
        RECT 0.96 0.48 1.03 0.615 ;
        RECT 0.36 0.4875 1.03 0.5575 ;
      LAYER via1 ;
        RECT 0.395 0.49 0.46 0.555 ;
        RECT 0.9625 0.515 1.0275 0.58 ;
    END
  END A
  PIN B
    DIRECTION INPUT ;
    USE SIGNAL ;
    PORT
      LAYER metal1 ;
        RECT 0.6825 0.6275 0.7475 0.7625 ;
        RECT 0.1725 0.6875 0.3075 0.7525 ;
      LAYER metal2 ;
        RECT 0.68 0.6275 0.75 0.7625 ;
        RECT 0.21 0.6875 0.75 0.7575 ;
        RECT 0.1725 0.685 0.3075 0.755 ;
      LAYER via1 ;
        RECT 0.2075 0.6875 0.2725 0.7525 ;
        RECT 0.6825 0.6625 0.7475 0.7275 ;
    END
  END B
  PIN y
    DIRECTION OUTPUT ;
    USE SIGNAL ;
    PORT
      LAYER metal1 ;
        RECT 0.8275 0.265 0.8925 0.9675 ;
        RECT 0.6375 0.8325 0.8925 0.8975 ;
        RECT 0.6375 0.8325 0.7025 1.315 ;
      LAYER metal2 ;
        RECT 0.825 0.8325 0.895 0.9675 ;
      LAYER via1 ;
        RECT 0.8275 0.8675 0.8925 0.9325 ;
    END
  END y
  OBS
    LAYER metal1 ;
      RECT 0.25 1.0425 0.315 1.335 ;
      RECT 0.0425 1.0425 0.315 1.1075 ;
      RECT 0.0425 0.2875 0.1075 1.1075 ;
      RECT 0.505 0.8075 0.57 0.9425 ;
      RECT 0.0425 0.8325 0.57 0.8975 ;
      RECT 0.0625 0.2675 0.1275 0.46 ;
      RECT 1.015 0.265 1.08 0.415 ;
      RECT 0.6375 0.275 0.7025 0.41 ;
    LAYER metal2 ;
      RECT 1.0125 0.275 1.0825 0.41 ;
      RECT 0.635 0.275 0.705 0.41 ;
      RECT 0.635 0.3125 1.0825 0.3825 ;
    LAYER via1 ;
      RECT 1.015 0.31 1.08 0.375 ;
      RECT 0.6375 0.31 0.7025 0.375 ;
  END
END xnor2

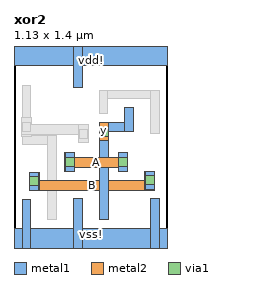
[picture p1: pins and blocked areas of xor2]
MACRO xor2
  CLASS CORE ;
  ORIGIN 0 -0.1 ;
  FOREIGN xor2 0 0.1 ;
  SIZE 1.13 BY 1.4 ;
  SYMMETRY X Y ;
  SITE CoreSite ;
  PIN vdd!
    DIRECTION INOUT ;
    USE POWER ;
    SHAPE ABUTMENT ;
    PORT
      LAYER metal1 ;
        RECT 0 1.4 1.13 1.6 ;
        RECT 0.44 1.24 0.505 1.6 ;
    END
  END vdd!
  PIN vss!
    DIRECTION INOUT ;
    USE GROUND ;
    SHAPE ABUTMENT ;
    PORT
      LAYER metal1 ;
        RECT 0 0 1.13 0.2 ;
        RECT 1.005 0 1.07 0.42 ;
        RECT 0.44 0 0.505 0.42 ;
        RECT 0.06 0 0.125 0.415 ;
    END
  END vss!
  PIN A
    DIRECTION INPUT ;
    USE SIGNAL ;
    PORT
      LAYER metal1 ;
        RECT 0.77 0.6225 0.835 0.7575 ;
        RECT 0.3775 0.6225 0.4425 0.7575 ;
      LAYER metal2 ;
        RECT 0.7675 0.6225 0.8375 0.7575 ;
        RECT 0.375 0.6525 0.8375 0.7225 ;
        RECT 0.375 0.6225 0.445 0.7575 ;
      LAYER via1 ;
        RECT 0.3775 0.6575 0.4425 0.7225 ;
        RECT 0.77 0.6575 0.835 0.7225 ;
    END
  END A
  PIN B
    DIRECTION INPUT ;
    USE SIGNAL ;
    PORT
      LAYER metal1 ;
        RECT 0.9675 0.4875 1.0325 0.6225 ;
        RECT 0.1175 0.48 0.1825 0.615 ;
      LAYER metal2 ;
        RECT 0.965 0.4825 1.035 0.6225 ;
        RECT 0.115 0.4825 1.035 0.5525 ;
        RECT 0.115 0.48 0.185 0.615 ;
      LAYER via1 ;
        RECT 0.1175 0.515 0.1825 0.58 ;
        RECT 0.9675 0.5225 1.0325 0.5875 ;
    END
  END B
  PIN y
    DIRECTION OUTPUT ;
    USE SIGNAL ;
    PORT
      LAYER metal1 ;
        RECT 0.8175 0.915 0.8825 1.09 ;
        RECT 0.63 0.915 0.8825 0.98 ;
        RECT 0.63 0.265 0.695 0.98 ;
      LAYER metal2 ;
        RECT 0.6275 0.845 0.6975 0.98 ;
      LAYER via1 ;
        RECT 0.63 0.88 0.695 0.945 ;
    END
  END y
  OBS
    LAYER metal1 ;
      RECT 0.6275 1.155 1.07 1.22 ;
      RECT 1.005 0.9025 1.07 1.22 ;
      RECT 0.6275 1.0475 0.6925 1.22 ;
      RECT 0.06 0.8175 0.125 1.255 ;
      RECT 0.06 0.8175 0.3125 0.8825 ;
      RECT 0.2475 0.265 0.3125 0.8825 ;
      RECT 0.48 0.83 0.545 0.965 ;
    LAYER metal2 ;
      RECT 0.0575 0.88 0.1275 1.015 ;
      RECT 0.0575 0.895 0.55 0.965 ;
      RECT 0.4775 0.83 0.55 0.965 ;
    LAYER via1 ;
      RECT 0.48 0.865 0.545 0.93 ;
      RECT 0.06 0.915 0.125 0.98 ;
  END
END xor2

END LIBRARY
